# OpenTallas memory compiler (tools/mem_compiler), ASAP7 abstract view, track-aligned v2 (build_aligned_v2.py)
VERSION 5.7 ;
BUSBITCHARS "[]" ;
DIVIDERCHAR "/" ;
PROPERTYDEFINITIONS
  MACRO width INTEGER ;
  MACRO depth INTEGER ;
  MACRO banks INTEGER ;
END PROPERTYDEFINITIONS
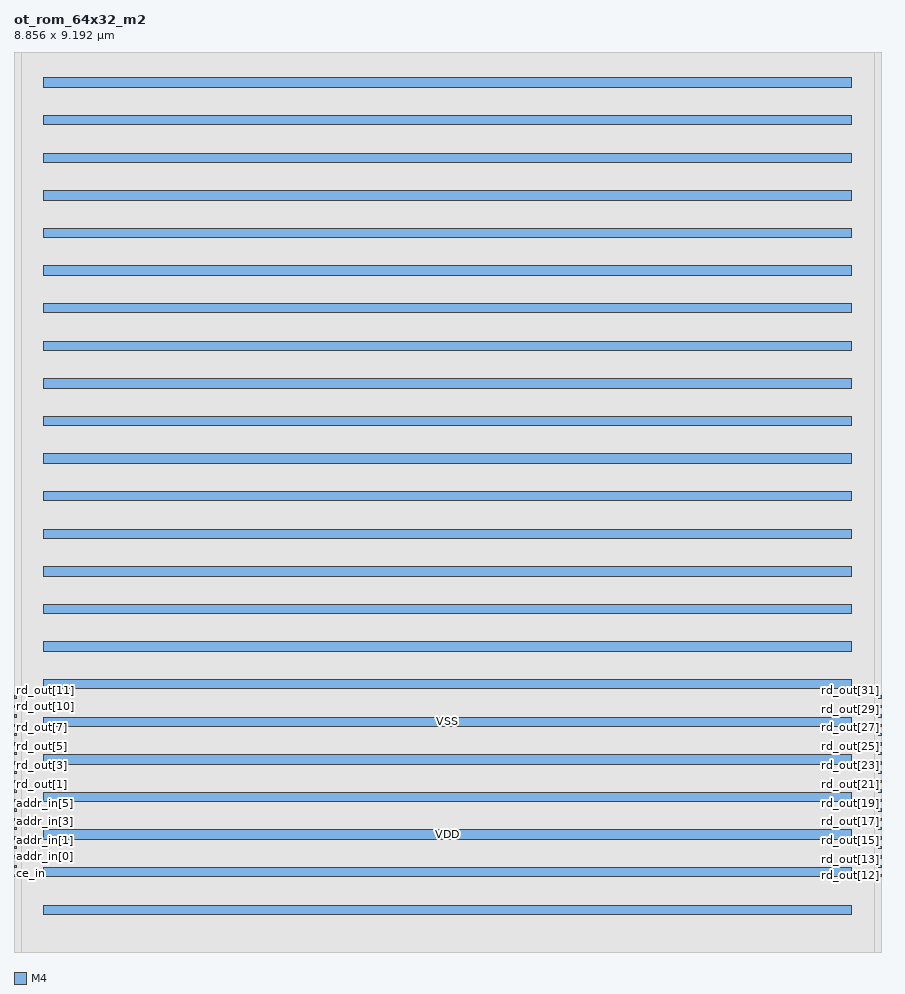
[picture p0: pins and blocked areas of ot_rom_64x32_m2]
MACRO ot_rom_64x32_m2
  PROPERTY width 32 ;
  PROPERTY depth 64 ;
  PROPERTY banks 1 ;
  FOREIGN ot_rom_64x32_m2 0 0 ;
  SYMMETRY X Y ;
  SIZE 8.856 BY 9.192 ;
  CLASS BLOCK ;
  PIN clk
    DIRECTION INPUT ;
    USE CLOCK ;
    SHAPE ABUTMENT ;
    PORT
      LAYER M4 ;
      RECT 0.000 0.768 0.024 0.792 ;
    END
  END clk
  PIN ce_in
    DIRECTION INPUT ;
    USE SIGNAL ;
    SHAPE ABUTMENT ;
    PORT
      LAYER M4 ;
      RECT 0.000 0.864 0.024 0.888 ;
    END
  END ce_in
  PIN addr_in[0]
    DIRECTION INPUT ;
    USE SIGNAL ;
    SHAPE ABUTMENT ;
    PORT
      LAYER M4 ;
      RECT 0.000 0.960 0.024 0.984 ;
    END
  END addr_in[0]
  PIN addr_in[1]
    DIRECTION INPUT ;
    USE SIGNAL ;
    SHAPE ABUTMENT ;
    PORT
      LAYER M4 ;
      RECT 0.000 1.056 0.024 1.080 ;
    END
  END addr_in[1]
  PIN addr_in[2]
    DIRECTION INPUT ;
    USE SIGNAL ;
    SHAPE ABUTMENT ;
    PORT
      LAYER M4 ;
      RECT 0.000 1.152 0.024 1.176 ;
    END
  END addr_in[2]
  PIN addr_in[3]
    DIRECTION INPUT ;
    USE SIGNAL ;
    SHAPE ABUTMENT ;
    PORT
      LAYER M4 ;
      RECT 0.000 1.248 0.024 1.272 ;
    END
  END addr_in[3]
  PIN addr_in[4]
    DIRECTION INPUT ;
    USE SIGNAL ;
    SHAPE ABUTMENT ;
    PORT
      LAYER M4 ;
      RECT 0.000 1.344 0.024 1.368 ;
    END
  END addr_in[4]
  PIN addr_in[5]
    DIRECTION INPUT ;
    USE SIGNAL ;
    SHAPE ABUTMENT ;
    PORT
      LAYER M4 ;
      RECT 0.000 1.440 0.024 1.464 ;
    END
  END addr_in[5]
  PIN rd_out[0]
    DIRECTION OUTPUT ;
    USE SIGNAL ;
    SHAPE ABUTMENT ;
    PORT
      LAYER M4 ;
      RECT 0.000 1.536 0.024 1.560 ;
    END
  END rd_out[0]
  PIN rd_out[1]
    DIRECTION OUTPUT ;
    USE SIGNAL ;
    SHAPE ABUTMENT ;
    PORT
      LAYER M4 ;
      RECT 0.000 1.632 0.024 1.656 ;
    END
  END rd_out[1]
  PIN rd_out[2]
    DIRECTION OUTPUT ;
    USE SIGNAL ;
    SHAPE ABUTMENT ;
    PORT
      LAYER M4 ;
      RECT 0.000 1.728 0.024 1.752 ;
    END
  END rd_out[2]
  PIN rd_out[3]
    DIRECTION OUTPUT ;
    USE SIGNAL ;
    SHAPE ABUTMENT ;
    PORT
      LAYER M4 ;
      RECT 0.000 1.824 0.024 1.848 ;
    END
  END rd_out[3]
  PIN rd_out[4]
    DIRECTION OUTPUT ;
    USE SIGNAL ;
    SHAPE ABUTMENT ;
    PORT
      LAYER M4 ;
      RECT 0.000 1.920 0.024 1.944 ;
    END
  END rd_out[4]
  PIN rd_out[5]
    DIRECTION OUTPUT ;
    USE SIGNAL ;
    SHAPE ABUTMENT ;
    PORT
      LAYER M4 ;
      RECT 0.000 2.016 0.024 2.040 ;
    END
  END rd_out[5]
  PIN rd_out[6]
    DIRECTION OUTPUT ;
    USE SIGNAL ;
    SHAPE ABUTMENT ;
    PORT
      LAYER M4 ;
      RECT 0.000 2.112 0.024 2.136 ;
    END
  END rd_out[6]
  PIN rd_out[7]
    DIRECTION OUTPUT ;
    USE SIGNAL ;
    SHAPE ABUTMENT ;
    PORT
      LAYER M4 ;
      RECT 0.000 2.208 0.024 2.232 ;
    END
  END rd_out[7]
  PIN rd_out[8]
    DIRECTION OUTPUT ;
    USE SIGNAL ;
    SHAPE ABUTMENT ;
    PORT
      LAYER M4 ;
      RECT 0.000 2.304 0.024 2.328 ;
    END
  END rd_out[8]
  PIN rd_out[9]
    DIRECTION OUTPUT ;
    USE SIGNAL ;
    SHAPE ABUTMENT ;
    PORT
      LAYER M4 ;
      RECT 0.000 2.400 0.024 2.424 ;
    END
  END rd_out[9]
  PIN rd_out[10]
    DIRECTION OUTPUT ;
    USE SIGNAL ;
    SHAPE ABUTMENT ;
    PORT
      LAYER M4 ;
      RECT 0.000 2.496 0.024 2.520 ;
    END
  END rd_out[10]
  PIN rd_out[11]
    DIRECTION OUTPUT ;
    USE SIGNAL ;
    SHAPE ABUTMENT ;
    PORT
      LAYER M4 ;
      RECT 0.000 2.592 0.024 2.616 ;
    END
  END rd_out[11]
  PIN rd_out[12]
    DIRECTION OUTPUT ;
    USE SIGNAL ;
    SHAPE ABUTMENT ;
    PORT
      LAYER M4 ;
      RECT 8.832 0.768 8.856 0.792 ;
    END
  END rd_out[12]
  PIN rd_out[13]
    DIRECTION OUTPUT ;
    USE SIGNAL ;
    SHAPE ABUTMENT ;
    PORT
      LAYER M4 ;
      RECT 8.832 0.864 8.856 0.888 ;
    END
  END rd_out[13]
  PIN rd_out[14]
    DIRECTION OUTPUT ;
    USE SIGNAL ;
    SHAPE ABUTMENT ;
    PORT
      LAYER M4 ;
      RECT 8.832 0.960 8.856 0.984 ;
    END
  END rd_out[14]
  PIN rd_out[15]
    DIRECTION OUTPUT ;
    USE SIGNAL ;
    SHAPE ABUTMENT ;
    PORT
      LAYER M4 ;
      RECT 8.832 1.056 8.856 1.080 ;
    END
  END rd_out[15]
  PIN rd_out[16]
    DIRECTION OUTPUT ;
    USE SIGNAL ;
    SHAPE ABUTMENT ;
    PORT
      LAYER M4 ;
      RECT 8.832 1.152 8.856 1.176 ;
    END
  END rd_out[16]
  PIN rd_out[17]
    DIRECTION OUTPUT ;
    USE SIGNAL ;
    SHAPE ABUTMENT ;
    PORT
      LAYER M4 ;
      RECT 8.832 1.248 8.856 1.272 ;
    END
  END rd_out[17]
  PIN rd_out[18]
    DIRECTION OUTPUT ;
    USE SIGNAL ;
    SHAPE ABUTMENT ;
    PORT
      LAYER M4 ;
      RECT 8.832 1.344 8.856 1.368 ;
    END
  END rd_out[18]
  PIN rd_out[19]
    DIRECTION OUTPUT ;
    USE SIGNAL ;
    SHAPE ABUTMENT ;
    PORT
      LAYER M4 ;
      RECT 8.832 1.440 8.856 1.464 ;
    END
  END rd_out[19]
  PIN rd_out[20]
    DIRECTION OUTPUT ;
    USE SIGNAL ;
    SHAPE ABUTMENT ;
    PORT
      LAYER M4 ;
      RECT 8.832 1.536 8.856 1.560 ;
    END
  END rd_out[20]
  PIN rd_out[21]
    DIRECTION OUTPUT ;
    USE SIGNAL ;
    SHAPE ABUTMENT ;
    PORT
      LAYER M4 ;
      RECT 8.832 1.632 8.856 1.656 ;
    END
  END rd_out[21]
  PIN rd_out[22]
    DIRECTION OUTPUT ;
    USE SIGNAL ;
    SHAPE ABUTMENT ;
    PORT
      LAYER M4 ;
      RECT 8.832 1.728 8.856 1.752 ;
    END
  END rd_out[22]
  PIN rd_out[23]
    DIRECTION OUTPUT ;
    USE SIGNAL ;
    SHAPE ABUTMENT ;
    PORT
      LAYER M4 ;
      RECT 8.832 1.824 8.856 1.848 ;
    END
  END rd_out[23]
  PIN rd_out[24]
    DIRECTION OUTPUT ;
    USE SIGNAL ;
    SHAPE ABUTMENT ;
    PORT
      LAYER M4 ;
      RECT 8.832 1.920 8.856 1.944 ;
    END
  END rd_out[24]
  PIN rd_out[25]
    DIRECTION OUTPUT ;
    USE SIGNAL ;
    SHAPE ABUTMENT ;
    PORT
      LAYER M4 ;
      RECT 8.832 2.016 8.856 2.040 ;
    END
  END rd_out[25]
  PIN rd_out[26]
    DIRECTION OUTPUT ;
    USE SIGNAL ;
    SHAPE ABUTMENT ;
    PORT
      LAYER M4 ;
      RECT 8.832 2.112 8.856 2.136 ;
    END
  END rd_out[26]
  PIN rd_out[27]
    DIRECTION OUTPUT ;
    USE SIGNAL ;
    SHAPE ABUTMENT ;
    PORT
      LAYER M4 ;
      RECT 8.832 2.208 8.856 2.232 ;
    END
  END rd_out[27]
  PIN rd_out[28]
    DIRECTION OUTPUT ;
    USE SIGNAL ;
    SHAPE ABUTMENT ;
    PORT
      LAYER M4 ;
      RECT 8.832 2.304 8.856 2.328 ;
    END
  END rd_out[28]
  PIN rd_out[29]
    DIRECTION OUTPUT ;
    USE SIGNAL ;
    SHAPE ABUTMENT ;
    PORT
      LAYER M4 ;
      RECT 8.832 2.400 8.856 2.424 ;
    END
  END rd_out[29]
  PIN rd_out[30]
    DIRECTION OUTPUT ;
    USE SIGNAL ;
    SHAPE ABUTMENT ;
    PORT
      LAYER M4 ;
      RECT 8.832 2.496 8.856 2.520 ;
    END
  END rd_out[30]
  PIN rd_out[31]
    DIRECTION OUTPUT ;
    USE SIGNAL ;
    SHAPE ABUTMENT ;
    PORT
      LAYER M4 ;
      RECT 8.832 2.592 8.856 2.616 ;
    END
  END rd_out[31]
  PIN VDD
    DIRECTION INOUT ;
    USE POWER ;
    PORT
      LAYER M4 ;
      RECT 0.300 0.384 8.556 0.480 ;
      RECT 0.300 1.152 8.556 1.248 ;
      RECT 0.300 1.920 8.556 2.016 ;
      RECT 0.300 2.688 8.556 2.784 ;
      RECT 0.300 3.456 8.556 3.552 ;
      RECT 0.300 4.224 8.556 4.320 ;
      RECT 0.300 4.992 8.556 5.088 ;
      RECT 0.300 5.760 8.556 5.856 ;
      RECT 0.300 6.528 8.556 6.624 ;
      RECT 0.300 7.296 8.556 7.392 ;
      RECT 0.300 8.064 8.556 8.160 ;
      RECT 0.300 8.832 8.556 8.928 ;
    END
  END VDD
  PIN VSS
    DIRECTION INOUT ;
    USE GROUND ;
    PORT
      LAYER M4 ;
      RECT 0.300 0.768 8.556 0.864 ;
      RECT 0.300 1.536 8.556 1.632 ;
      RECT 0.300 2.304 8.556 2.400 ;
      RECT 0.300 3.072 8.556 3.168 ;
      RECT 0.300 3.840 8.556 3.936 ;
      RECT 0.300 4.608 8.556 4.704 ;
      RECT 0.300 5.376 8.556 5.472 ;
      RECT 0.300 6.144 8.556 6.240 ;
      RECT 0.300 6.912 8.556 7.008 ;
      RECT 0.300 7.680 8.556 7.776 ;
      RECT 0.300 8.448 8.556 8.544 ;
    END
  END VSS
  OBS
    LAYER M1 ;
    RECT 0 0 8.856 9.192 ;
    LAYER M2 ;
    RECT 0 0 8.856 9.192 ;
    LAYER M3 ;
    RECT 0 0 8.856 9.192 ;
    LAYER M4 ;
    RECT 0.072 0 8.784 9.192 ;
  END
END ot_rom_64x32_m2

END LIBRARY
